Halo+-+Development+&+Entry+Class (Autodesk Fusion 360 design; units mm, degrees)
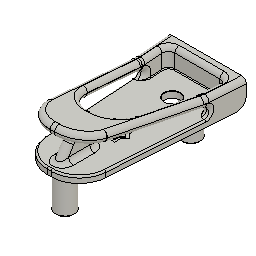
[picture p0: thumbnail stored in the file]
description: Part Number
part number: Final Halo For Development Class
base_feature "Base Feature"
